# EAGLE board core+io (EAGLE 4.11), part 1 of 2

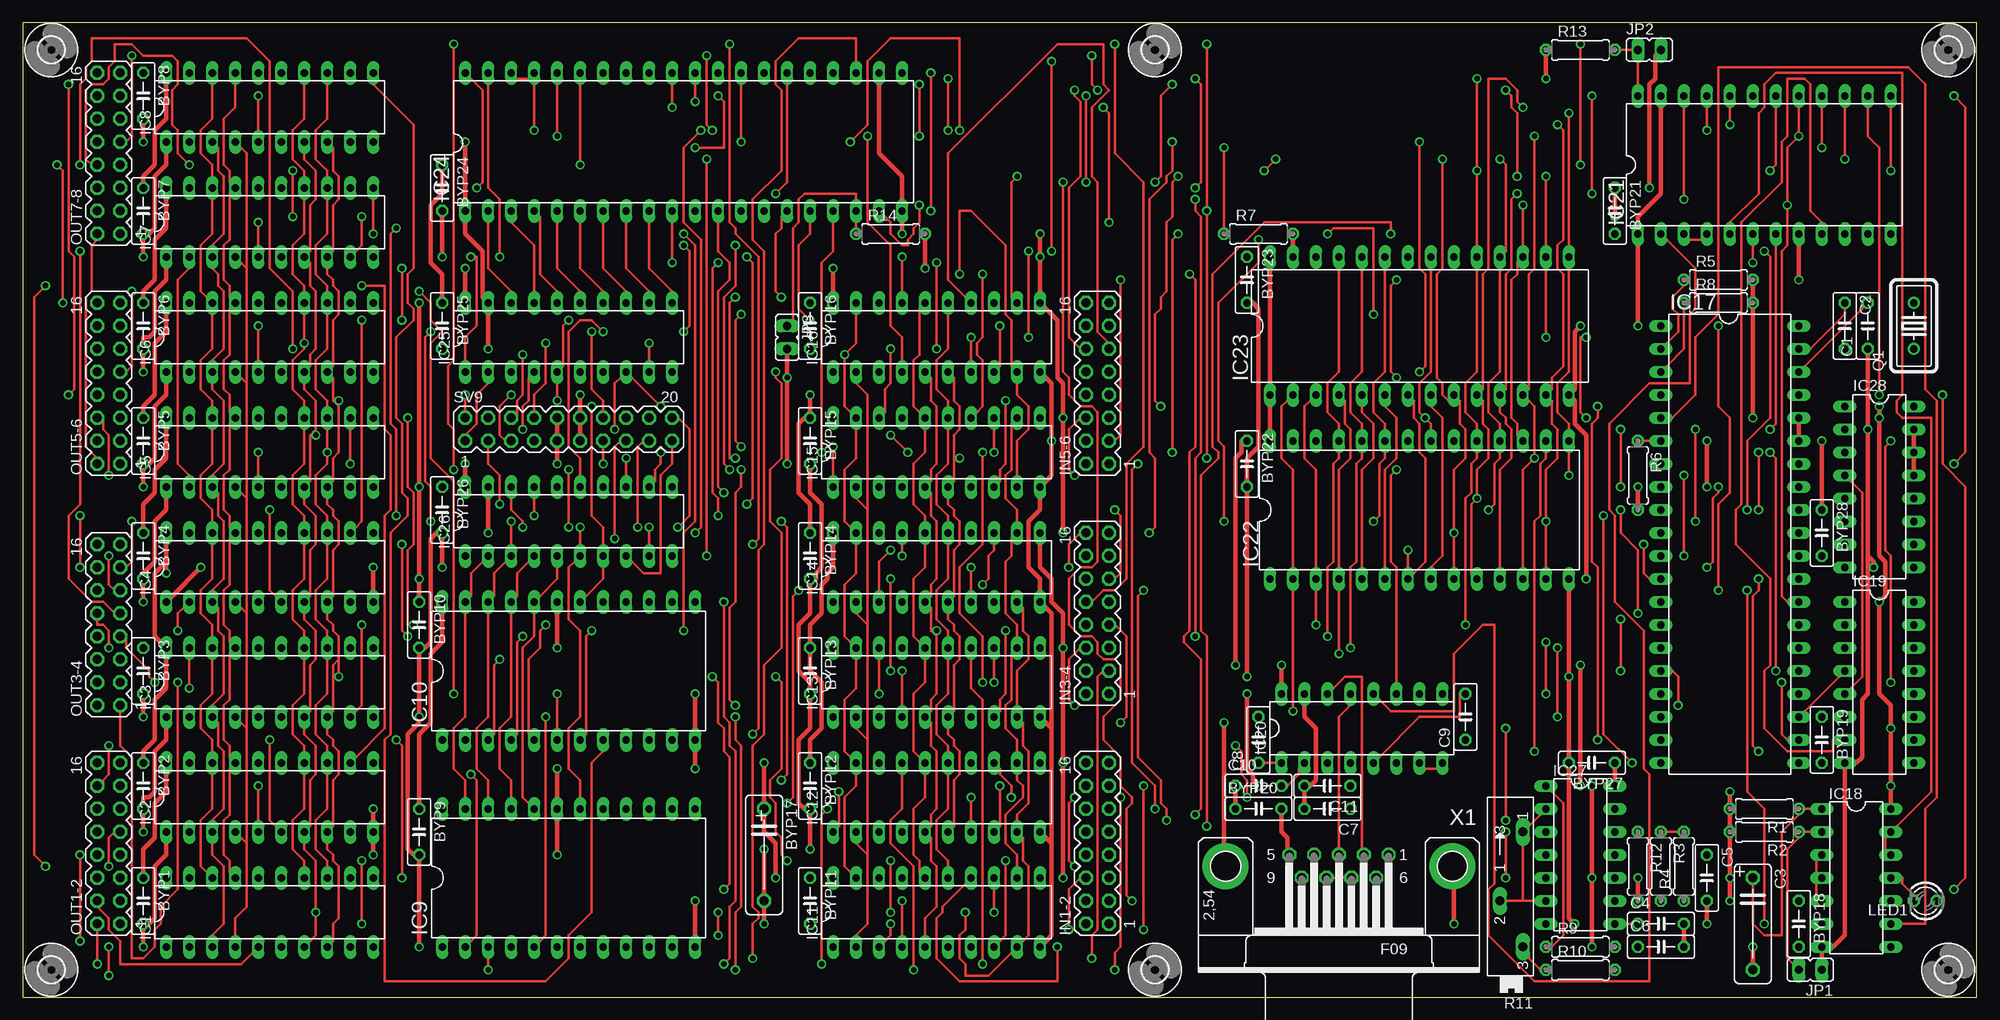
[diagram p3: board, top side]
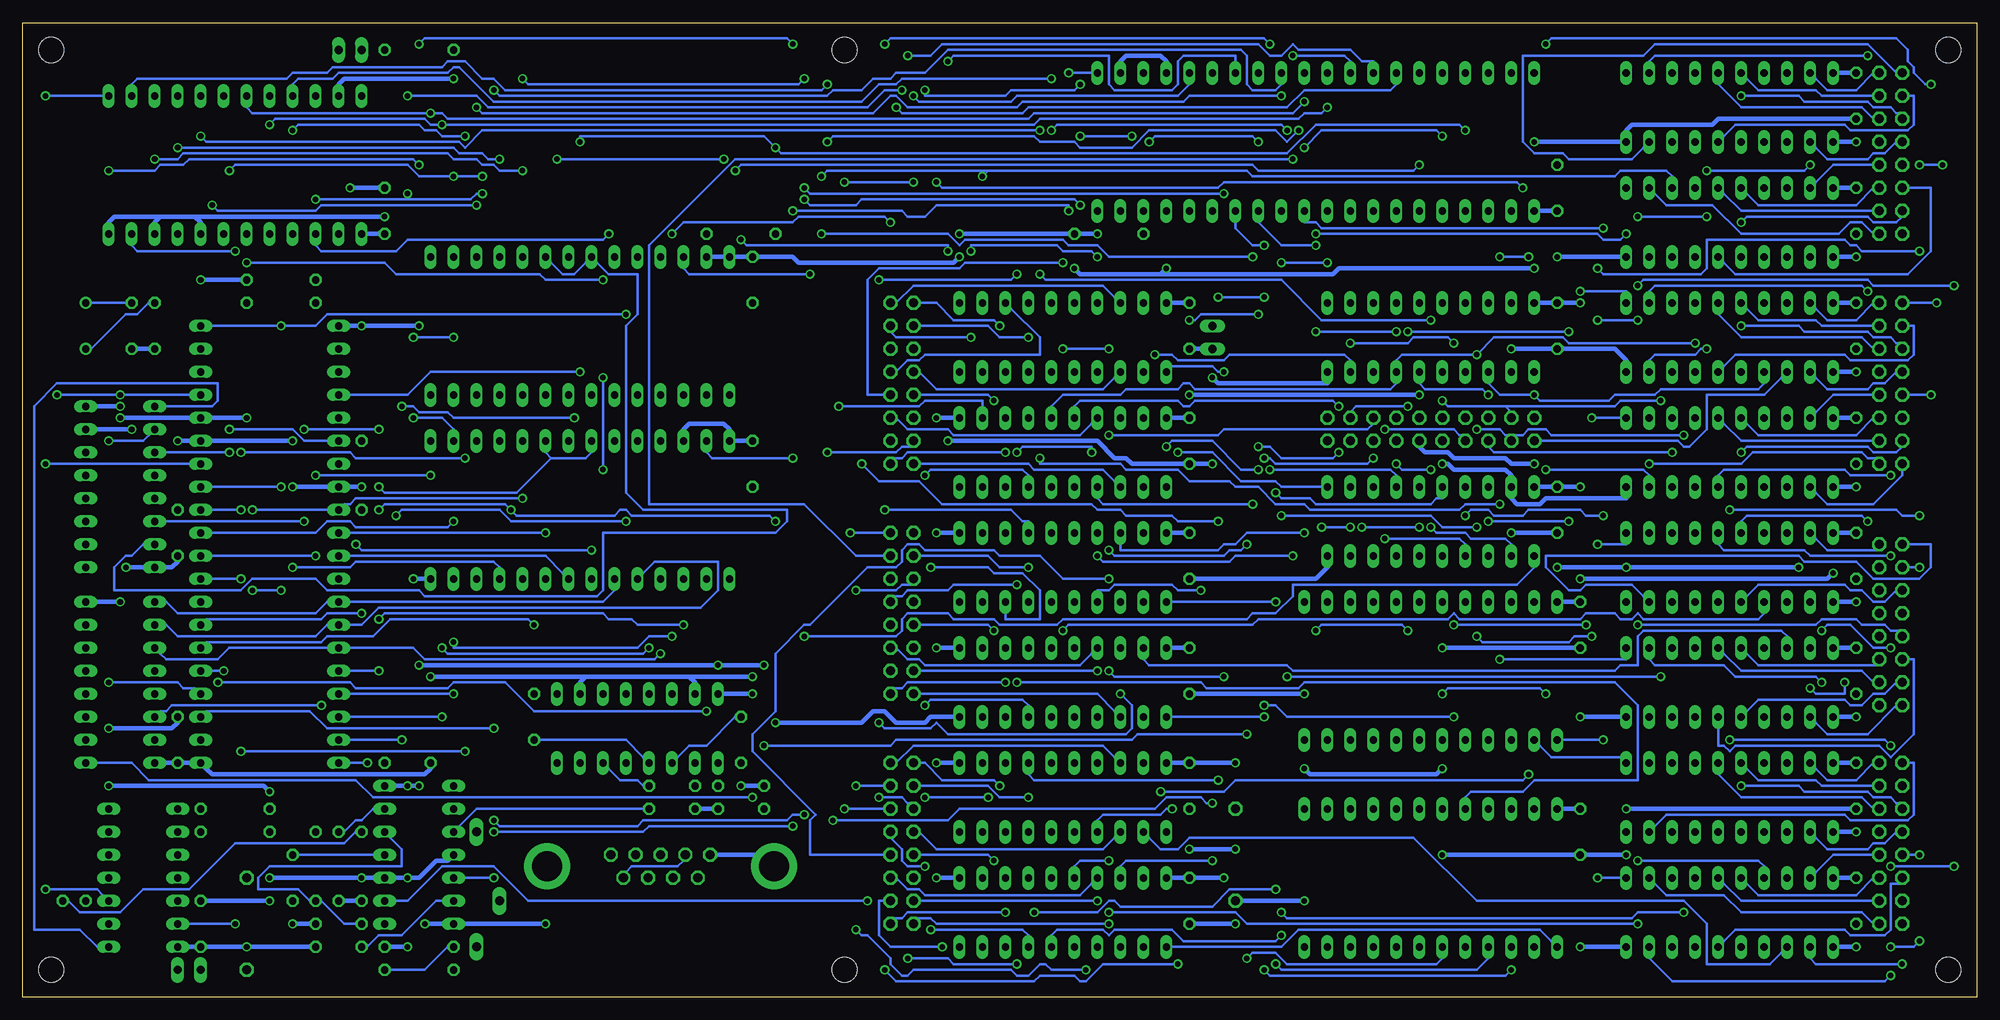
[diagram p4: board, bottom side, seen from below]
Size 215.88 x 107.62 mm. Coordinates in mm from the lower left corner, seen from the top.
Outline: 0,0 215.88,0 215.88,107.62 0,107.62 0,0
Copper layers (1*16): Top 0.035mm / dielectric 1.5mm / Bottom 0.035mm
Design rules "default": minimum track width 10mil, minimum drill 24mil, track to track 8mil, track to pad 8mil, pad to pad 8mil, via to via 8mil, smd to smd 8mil, copper to edge 40mil, drill to drill 8mil, minimum pad ring 10mil, minimum via ring 8mil, stop-mask expansion 4mil, vias tented up to drill 0mil, thermal gap 10mil
Net classes: 1 Power: width 0.508 mm, drill 0.254 mm, clearance 0.254 mm

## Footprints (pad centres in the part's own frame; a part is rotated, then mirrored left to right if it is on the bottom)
C050-025X075 = drill 0.813 octagon: 1 -2.54,0; 2 2.54,0
C102-043X133 = drill 1.016 octagon: 1 -5.08,0; 2 5.08,0
DIL20 = drill 0.813 long: 1 -11.43,-3.81; 2 -8.89,-3.81; 3 -6.35,-3.81; 4 -3.81,-3.81; 5 -1.27,-3.81; 6 1.27,-3.81; 7 3.81,-3.81; 8 6.35,-3.81; 9 8.89,-3.81; 10 11.43,-3.81; 11 11.43,3.81; 12 8.89,3.81; 13 6.35,3.81; 14 3.81,3.81; 15 1.27,3.81; 16 -1.27,3.81; 17 -3.81,3.81; 18 -6.35,3.81; 19 -8.89,3.81; 20 -11.43,3.81
DIL24-6 = drill 0.813 long: 1 -13.97,-7.62; 2 -11.43,-7.62; 3 -8.89,-7.62; 4 -6.35,-7.62; 5 -3.81,-7.62; 6 -1.27,-7.62; 7 1.27,-7.62; 8 3.81,-7.62; 9 6.35,-7.62; 10 8.89,-7.62; 11 11.43,-7.62; 12 13.97,-7.62; 13 13.97,7.62; 14 11.43,7.62; 15 8.89,7.62; 16 6.35,7.62; 17 3.81,7.62; 18 1.27,7.62; 19 -1.27,7.62; 20 -3.81,7.62; 21 -6.35,7.62; 22 -8.89,7.62; 23 -11.43,7.62; 24 -13.97,7.62
DIL40 = drill 0.813 long: 1 -24.13,-7.62; 2 -21.59,-7.62; 3 -19.05,-7.62; 4 -16.51,-7.62; 5 -13.97,-7.62; 6 -11.43,-7.62; 7 -8.89,-7.62; 8 -6.35,-7.62; 9 -3.81,-7.62; 10 -1.27,-7.62; 11 1.27,-7.62; 12 3.81,-7.62; 13 6.35,-7.62; 14 8.89,-7.62; 15 11.43,-7.62; 16 13.97,-7.62; 17 16.51,-7.62; 18 19.05,-7.62; 19 21.59,-7.62; 20 24.13,-7.62; 21 24.13,7.62; 22 21.59,7.62; 23 19.05,7.62; 24 16.51,7.62; 25 13.97,7.62; 26 11.43,7.62; 27 8.89,7.62; 28 6.35,7.62; 29 3.81,7.62; 30 1.27,7.62; 31 -1.27,7.62; 32 -3.81,7.62; 33 -6.35,7.62; 34 -8.89,7.62; 35 -11.43,7.62; 36 -13.97,7.62; 37 -16.51,7.62; 38 -19.05,7.62; 39 -21.59,7.62; 40 -24.13,7.62
DIL14 = drill 0.813 long: 1 -7.62,-3.81; 2 -5.08,-3.81; 3 -2.54,-3.81; 4 0,-3.81; 5 2.54,-3.81; 6 5.08,-3.81; 7 7.62,-3.81; 8 7.62,3.81; 9 5.08,3.81; 10 2.54,3.81; 11 0,3.81; 12 -2.54,3.81; 13 -5.08,3.81; 14 -7.62,3.81
DIL16 = drill 0.813 long: 1 -8.89,-3.81; 2 -6.35,-3.81; 3 -3.81,-3.81; 4 -1.27,-3.81; 5 1.27,-3.81; 6 3.81,-3.81; 7 6.35,-3.81; 8 8.89,-3.81; 9 8.89,3.81; 10 6.35,3.81; 11 3.81,3.81; 12 1.27,3.81; 13 -1.27,3.81; 14 -3.81,3.81; 15 -6.35,3.81; 16 -8.89,3.81
DIL24 = drill 0.813 long: 1 -13.97,-7.62; 2 -11.43,-7.62; 3 -8.89,-7.62; 4 -6.35,-7.62; 5 -3.81,-7.62; 6 -1.27,-7.62; 7 1.27,-7.62; 8 3.81,-7.62; 9 6.35,-7.62; 10 8.89,-7.62; 11 11.43,-7.62; 12 13.97,-7.62; 13 13.97,7.62; 14 11.43,7.62; 15 8.89,7.62; 16 6.35,7.62; 17 3.81,7.62; 18 1.27,7.62; 19 -1.27,7.62; 20 -3.81,7.62; 21 -6.35,7.62; 22 -8.89,7.62; 23 -11.43,7.62; 24 -13.97,7.62
DIL28-6 = drill 0.813 long: 1 -16.51,-7.62; 2 -13.97,-7.62; 3 -11.43,-7.62; 4 -8.89,-7.62; 5 -6.35,-7.62; 6 -3.81,-7.62; 7 -1.27,-7.62; 8 1.27,-7.62; 9 3.81,-7.62; 10 6.35,-7.62; 11 8.89,-7.62; 12 11.43,-7.62; 13 13.97,-7.62; 14 16.51,-7.62; 15 16.51,7.62; 16 13.97,7.62; 17 11.43,7.62; 18 8.89,7.62; 19 6.35,7.62; 20 3.81,7.62; 21 1.27,7.62; 22 -1.27,7.62; 23 -3.81,7.62; 24 -6.35,7.62; 25 -8.89,7.62; 26 -11.43,7.62; 27 -13.97,7.62; 28 -16.51,7.62
MA08-2 = drill 1.016 octagon: 1 -8.89,-1.27; 2 -8.89,1.27; 3 -6.35,-1.27; 4 -6.35,1.27; 5 -3.81,-1.27; 6 -3.81,1.27; 7 -1.27,-1.27; 8 -1.27,1.27; 9 1.27,-1.27; 10 1.27,1.27; 11 3.81,-1.27; 12 3.81,1.27; 13 6.35,-1.27; 14 6.35,1.27; 15 8.89,-1.27; 16 8.89,1.27
JP1 = drill 0.914 long: 1 0,-1.27; 2 0,1.27
LED3MM = drill 0.813 octagon: A -1.27,0; K 1.27,0
HC18U-V = drill 0.813 round: 1 -2.54,0; 2 2.54,0
0207/7 = drill 0.813 octagon: 1 -3.81,0; 2 3.81,0
SP19L = drill 1.016 long: A 5.715,-1.27; E -6.985,-1.27; S -1.905,1.27
MA10-2 = drill 1.016 octagon: 1 -11.43,-1.27; 2 -11.43,1.27; 3 -8.89,-1.27; 4 -8.89,1.27; 5 -6.35,-1.27; 6 -6.35,1.27; 7 -3.81,-1.27; 8 -3.81,1.27; 9 -1.27,-1.27; 10 -1.27,1.27; 11 1.27,-1.27; 12 1.27,1.27; 13 3.81,-1.27; 14 3.81,1.27; 15 6.35,-1.27; 16 6.35,1.27; 17 8.89,-1.27; 18 8.89,1.27; 19 11.43,-1.27; 20 11.43,1.27
2,8 = hole 2.8: 0,0
F09HP = drill 1.016 octagon: 1 -5.486,-1.27; 2 -2.743,-1.27; 3 0,-1.27; 4 2.743,-1.27; 5 5.486,-1.27; 6 -4.115,1.27; 7 -1.372,1.27; 8 1.372,1.27; 9 4.115,1.27 | drill 3.302 pad 5.08 round: G1 -12.522,0; G2 12.522,0

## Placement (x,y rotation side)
BYP1  .01uf  [C050-025X075]  13.33,10.63 270 top
BYP2  .01uf  [C050-025X075]  13.33,23.33 270 top
BYP3  .01uf  [C050-025X075]  13.33,36.03 270 top
BYP4  .01uf  [C050-025X075]  13.33,48.73 270 top
BYP5  .01uf  [C050-025X075]  13.33,61.43 270 top
BYP6  .01uf  [C050-025X075]  13.33,74.13 270 top
BYP7  .01uf  [C050-025X075]  13.33,86.83 270 top
BYP8  .01uf  [C050-025X075]  13.33,99.53 270 top
BYP9  .01uf  [C050-025X075]  43.81,18.25 270 top
BYP10  .01uf  [C050-025X075]  43.81,41.11 270 top
BYP11  .01uf  [C050-025X075]  86.99,10.63 270 top
BYP12  .01uf  [C050-025X075]  86.99,23.33 270 top
BYP13  .01uf  [C050-025X075]  86.99,36.03 270 top
BYP14  .01uf  [C050-025X075]  86.99,48.73 270 top
BYP15  .01uf  [C050-025X075]  86.99,61.43 270 top
BYP16  .01uf  [C050-025X075]  86.99,74.13 270 top
BYP17  100uf 25V  [C102-043X133]  81.91,15.71 270 top
BYP18  .01uf  [C050-025X075]  196.21,8.09 270 top
BYP19  .01uf  [C050-025X075]  198.75,28.41 270 top
BYP20  .01uf  [C050-025X075]  136.52,20.79 0 top
BYP21  .01uf  [C050-025X075]  175.89,86.83 270 top
BYP22  .01uf  [C050-025X075]  135.25,58.89 270 top
BYP23  .01uf  [C050-025X075]  135.25,79.21 270 top
BYP24  .01uf  [C050-025X075]  46.35,89.37 270 top
BYP25  .01uf  [C050-025X075]  46.35,74.13 270 top
BYP26  .01uf  [C050-025X075]  46.35,53.81 270 top
BYP27  .01uf  [C050-025X075]  173.35,25.87 180 top
BYP28  .01uf  [C050-025X075]  198.75,51.27 270 top
C1  27pf  [C050-025X075]  203.83,74.13 90 top
C2  27pf  [C050-025X075]  201.29,74.13 270 top
C3  22uf  [C102-043X133]  191.13,8.09 270 top
C4  0.1uf  [C050-025X075]  180.97,8.09 0 top
C5  .01uf  [C050-025X075]  186.05,13.17 270 top
C6  330pf  [C050-025X075]  180.97,5.55 0 top
C7  .01uf  [C050-025X075]  144.14,20.79 180 top
C8  0.1uf  [C050-025X075]  136.52,28.41 90 top
C9  0.1uf  [C050-025X075]  159.38,30.95 90 top
C10  0.1uf  [C050-025X075]  136.52,23.33 0 top
C11  0.1uf  [C050-025X075]  144.14,23.33 180 top
IC1  74LS374N  [DIL20]  27.3,9.36 0 top
IC2  74LS374N  [DIL20]  27.3,22.06 0 top
IC3  74LS374N  [DIL20]  27.3,34.76 0 top
IC4  74LS374N  [DIL20]  27.3,47.46 0 top
IC5  74LS374N  [DIL20]  27.3,60.16 0 top
IC6  74LS374N  [DIL20]  27.3,72.86 0 top
IC7  74LS374N  [DIL20]  27.3,85.56 0 top
IC8  74LS374N  [DIL20]  27.3,98.26 0 top
IC9  74154N  [DIL24-6]  60.32,13.17 0 top
IC10  74154N  [DIL24-6]  60.32,36.03 0 top
IC11  74LS373N  [DIL20]  100.96,9.36 0 top
IC12  74LS373N  [DIL20]  100.96,22.06 0 top
IC13  74LS373N  [DIL20]  100.96,34.76 0 top
IC14  74LS373N  [DIL20]  100.96,47.46 0 top
IC15  74LS373N  [DIL20]  100.96,60.16 0 top
IC16  74LS373N  [DIL20]  100.96,72.86 0 top
IC17  [DIL40]  188.59,50 270 top
IC18  74LS132N  [DIL14]  202.56,13.17 270 top
IC19  74LS138N  [DIL16]  205.1,34.76 270 top
IC20  MAX232  [DIL16]  147.95,29.68 0 top
IC21  [DIL24]  192.4,91.91 0 top
IC22  [DIL28-6]  154.3,53.81 0 top
IC23  27C128P  [DIL28-6]  154.3,74.13 0 top
IC24  [DIL40]  73.02,94.45 0 top
IC25  74LS245N  [DIL20]  60.32,72.86 0 top
IC26  74LS245N  [DIL20]  60.32,52.54 0 top
IC27  LM556N  [DIL14]  172.08,15.71 270 top
IC28  74LS139N  [DIL16]  205.1,56.35 270 top
IN1-2  [MA08-2]  118.74,16.98 90 top
IN3-4  [MA08-2]  118.74,42.38 90 top
IN5-6  [MA08-2]  118.74,67.78 90 top
JP1  RESET  [JP1]  197.48,3.01 90 top
JP2  DEBUG  [JP1]  179.7,104.61 270 top
JP3  CB1  [JP1]  84.45,72.86 180 top
LED1  [LED3MM]  210.18,10.63 180 top
OUT1-2  [MA08-2]  9.52,16.98 90 top
OUT3-4  [MA08-2]  9.52,41.11 90 top
OUT5-6  [MA08-2]  9.52,67.78 90 top
OUT7-8  [MA08-2]  9.52,93.18 90 top
Q1  4Mhz  [HC18U-V]  208.91,74.13 90 top
R1  10K  [0207/7]  192.4,20.79 180 top
R2  10K  [0207/7]  192.4,18.25 180 top
R3  100K  [0207/7]  180.97,14.44 270 top
R4  100K  [0207/7]  183.51,14.44 90 top
R5  3.3K  [0207/7]  187.32,79.21 0 top
R6  3.3K  [0207/7]  178.43,57.62 270 top
R7  3.3K  [0207/7]  136.52,84.29 0 top
R8  3.3K  [0207/7]  187.32,76.67 0 top
R9  1.8K  [0207/7]  172.08,5.55 0 top
R10  10K  [0207/7]  172.08,3.01 0 top
R11  10K  [SP19L]  164.46,12.54 90 top
R12  270  [0207/7]  178.43,14.44 270 top
R13  1K  [0207/7]  172.08,104.61 0 top
R14  3.3K  [0207/7]  95.88,84.29 0 top
SV9  [MA10-2]  60.32,62.7 0 top
U$1  [2,8]  125.09,3.01 0 top
U$2  [2,8]  125.09,104.61 0 top
U$3  [2,8]  3.17,104.61 0 top
U$4  [2,8]  3.17,3.01 0 top
U$5  [2,8]  212.72,104.61 0 top
U$6  [2,8]  212.72,3.01 0 top
X1  [F09HP]  145.41,14.44 180 top

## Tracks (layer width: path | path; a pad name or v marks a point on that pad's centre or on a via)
89AB\  (via drill 0.61)
  Top 0.254: v184.78,62.7 v184.78,52.54 | v176.53,56.35 v176.53,62.7
  Bottom 0.254: 157.47,59.52 158.11,60.16 IC22.20 | 157.47,59.52 153.66,59.52 153.03,60.16 IC22.22 | v184.78,52.54 200.02,52.54 IC28.6 | v176.53,62.7 v184.78,62.7 | v176.53,56.35 175.89,55.71 161.28,55.71 157.47,59.52
A00  (via drill 0.61)
  Top 0.254: IC22.10 160.01,46.82 160.01,54.45 v160.65,55.08 160.65,58.25 161.92,59.52 161.92,62.7 161.28,63.34 161.28,65.88 IC23.10 161.28,67.14 161.28,79.84 161.92,80.48 161.92,101.44 163.82,101.44 165.09,100.16 165.09,98.89 v165.73,98.26 | v192.4,82.39 193.03,81.75 193.03,63.97 190.5,61.43 v190.5,53.81 | v59.05,95.08 59.05,100.8 IC24.36 | v74.29,93.81 77.46,93.81 77.46,98.89 v76.83,99.53
  Bottom 0.254: v160.65,55.08 179.06,55.08 179.7,54.45 180.34,54.45 IC17.9 182.24,53.81 v190.5,53.81 | v192.4,82.39 203.19,82.39 203.83,83.02 IC21.11 | v59.05,95.08 59.69,95.72 72.38,95.72 v74.29,93.81 | v76.83,99.53 86.99,99.53 87.62,98.89 105.41,98.89 106.04,98.26 118.1,98.26 119.38,99.53 120.01,99.53 121.91,97.62 165.09,97.62 v165.73,98.26
A01  (via drill 0.61)
  Top 0.254: IC22.9 158.11,47.46 v158.11,51.27 158.11,58.25 159.38,59.52 159.38,62.7 158.75,63.34 158.75,65.88 IC23.9 157.47,65.88 156.84,66.51 156.84,67.78 156.2,68.41 156.2,79.84 156.84,80.48 v156.84,92.55 | v61.59,91.91 61.59,100.8 IC24.35 | v137.16,91.28 v138.42,92.55
  Bottom 0.254: v61.59,91.91 62.23,91.28 79.37,91.28 80,91.91 136.52,91.91 v137.16,91.28 | v138.42,92.55 v156.84,92.55 | v158.11,51.27 179.7,51.27 IC17.10
A02
  Top 0.254: IC23.8 155.57,65.24 156.84,63.97 156.84,48.73 155.57,47.46 IC22.8
  Bottom 0.254: IC22.8 156.2,46.82 158.11,48.73 179.7,48.73 IC17.11
A03  (via drill 0.61)
  Top 0.254: IC23.7 153.66,65.88 153.66,63.97 154.3,63.34 154.3,60.16 154.94,59.52 154.94,48.09 153.66,46.82 IC22.7 153.03,47.46 v153.03,49.37 | v179.06,50 179.06,46.82 179.7,46.19 IC17.12
  Bottom 0.254: v179.06,50 178.43,49.37 v153.03,49.37
A04
  Top 0.254: IC23.6 150.49,65.24 151.76,63.97 151.76,59.52 150.49,58.25 150.49,47.46 IC22.6
  Bottom 0.254: IC19.1 200.02,43.65 198.75,42.38 183.51,42.38 182.24,43.65 IC17.13 179.7,43.65 151.76,43.65 150.49,44.92 IC22.6
A05
  Top 0.254: IC22.5 147.95,47.46 147.95,58.25 149.22,59.52 149.22,63.34 147.95,64.61 147.95,65.24 IC23.5
  Bottom 0.254: IC19.2 200.02,41.11 198.75,39.84 183.51,39.84 182.24,41.11 IC17.14 179.7,41.11 178.43,41.11 176.53,43.02 140.97,43.02 139.06,44.92 139.06,48.09 146.04,48.09 147.31,46.82 IC22.5
A06  (via drill 0.61)
  Top 0.254: IC23.4 146.04,65.88 146.04,63.34 146.68,62.7 146.68,59.52 145.41,58.25 145.41,47.46 IC22.4 145.41,44.92 v145.41,37.94
  Bottom 0.254: IC19.3 200.66,37.94 200.02,37.3 194.31,37.3 193.03,38.57 182.24,38.57 IC17.15 179.7,38.57 172.72,38.57 171.44,37.3 146.04,37.3 v145.41,37.94
A07  (via drill 0.61)
  Top 0.254: IC23.3 142.23,65.88 141.6,65.24 141.6,59.52 142.87,58.25 142.87,47.46 IC22.3 142.87,44.92 v142.87,41.11 | v182.88,32.22 182.88,35.39 182.24,36.03 IC17.16 | v176.53,41.74 v176.53,36.03
  Bottom 0.254: v182.88,32.22 199.38,32.22 200.02,31.58 200.66,31.58 IC19.6 | v142.87,41.11 147.95,41.11 148.59,41.74 151.12,41.74 151.76,42.38 175.89,42.38 v176.53,41.74 | v176.53,36.03 179.7,36.03 IC17.16
A08  (via drill 0.61)
  Top 0.254: IC23.25 145.41,80.48 145.41,69.05 144.14,67.78 144.14,64.61 145.41,63.34 145.41,62.7 IC22.25 145.41,60.16 145.41,59.52 144.78,58.89 144.78,48.09 144.14,47.46 v144.14,39.84 | v168.27,39.2 v168.27,33.49
  Bottom 0.254: v168.27,33.49 179.7,33.49 IC17.17 | v168.27,39.2 168.27,38.57 147.95,38.57 146.68,39.84 v144.14,39.84
A09  (via drill 0.61)
  Top 0.254: IC23.24 147.95,80.48 147.95,69.05 146.68,67.78 146.68,64.61 147.95,63.34 147.95,62.7 IC22.24 147.95,60.16 147.95,59.52 147.31,58.89 147.31,48.09 146.68,47.46 v146.68,38.57 | v169.54,38.57 v169.54,30.95
  Bottom 0.254: v169.54,30.95 179.7,30.95 IC17.18 | v169.54,38.57 168.91,37.94 147.31,37.94 v146.68,38.57
A10  (via drill 0.61)
  Top 0.254: IC23.21 155.57,80.48 155.57,69.05 154.3,67.78 154.3,64.61 v154.94,63.97 155.57,63.34 155.57,62.7 IC22.21 | v173.98,28.41 173.98,47.46 173.35,48.09 173.35,63.34 173.98,63.97 v173.98,65.24
  Bottom 0.254: v173.98,28.41 179.7,28.41 IC17.19 | v173.98,65.24 172.72,65.24 172.08,64.61 168.91,64.61 168.27,63.97 v154.94,63.97
A11  (via drill 0.61)
  Top 0.254: IC23.23 150.49,80.48 150.49,69.05 149.22,67.78 149.22,64.61 150.49,63.34 150.49,62.7 IC22.23 150.49,60.16 150.49,59.52 149.85,58.89 149.85,53.17 v149.22,52.54 | v177.79,25.87 174.62,29.04 v174.62,53.17
  Bottom 0.254: v177.79,25.87 179.7,25.87 IC17.20 | v174.62,53.17 173.98,53.81 163.19,53.81 161.92,52.54 v149.22,52.54
A12  (via drill 0.61)
  Top 0.254: IC23.2 139.69,65.88 139.06,65.24 139.06,59.52 140.33,58.25 140.33,47.46 IC22.2 140.33,44.92 v140.33,31.58 | v194.31,34.76 194.31,29.04 194.94,28.41 IC17.22
  Bottom 0.254: v194.31,34.76 179.7,34.76 179.06,34.12 168.91,34.12 168.27,34.76 162.56,34.76 159.38,31.58 v140.33,31.58
A13  (via drill 0.61)
  Top 0.254: v128.9,79.84 129.53,79.21 129.53,60.8 128.9,60.16 128.9,40.48 128.27,39.84 128.27,39.2 130.17,37.3 130.17,20.79 v129.53,20.15 | v163.82,19.52 v163.82,29.68 | IC19.4 200.66,35.39 196.84,31.58 IC17.23
  Bottom 0.254: v128.9,79.84 142.23,79.84 142.87,80.48 IC23.26 | v129.53,20.15 130.81,20.15 131.44,19.52 147.31,19.52 147.95,18.88 163.19,18.88 v163.82,19.52 | v163.82,29.68 182.24,29.68 184.14,31.58 195.57,31.58 IC17.23
A14  (via drill 0.61)
  Top 0.254: v206.37,34.76 206.37,48.73 205.73,49.37 205.73,60.8 v206.37,61.43
  Bottom 0.254: v206.37,34.76 198.75,34.76 198.12,34.12 196.84,34.12 IC17.24 | v206.37,61.43 202.56,61.43 201.92,62.06 IC28.2
A15  (via drill 0.61)
  Top 0.254: v193.67,36.03 193.67,59.52 v193.03,60.16
  Bottom 0.254: v193.67,36.03 194.94,36.03 IC17.25 | v193.03,60.16 200.02,60.16 IC28.3
CB1
  Top 0.254: R14.1 92.07,84.92 92.07,85.56 IC24.18 92.07,88.1 92.07,88.73 86.35,88.73 85.72,88.1 85.72,85.56 85.08,84.92 85.08,74.77 JP3.1
CDEF\
  Bottom 0.254: IC23.20 157.47,81.11 156.2,79.84 154.94,79.84 153.66,81.11 IC23.22 152.39,81.11 151.12,79.84 147.95,79.84 147.95,75.4 149.22,74.13 149.22,55.71 147.31,53.81 131.44,53.81 131.44,52.54 132.71,51.27 151.76,51.27 151.76,44.92 152.39,44.28 171.44,44.28 172.08,44.92 182.24,44.92 183.51,46.19 190.5,46.19 191.76,44.92 205.73,44.92 205.73,47.46 204.47,48.73 203.83,48.73 202.56,50 IC28.7
D0  (via drill 0.61)
  Top 0.254: IC22.11 163.19,47.46 163.19,58.25 164.46,59.52 164.46,62.7 163.82,63.34 163.82,63.97 163.19,64.61 163.19,65.24 IC23.11 163.82,67.14 163.82,79.84 164.46,80.48 164.46,88.1 v165.09,88.73 | v183.51,88.1 183.51,98.26 IC21.22 | v118.1,103.97 118.1,100.8 v118.74,100.16 | v173.35,88.73 v173.35,99.53 | v187.32,56.35 187.32,55.71 186.69,55.08 186.69,48.09 v186.05,47.46
  Bottom 0.254: 173.35,88.1 166.37,88.1 165.73,88.73 v165.09,88.73 | 173.35,88.1 v183.51,88.1 | v118.1,103.97 115.56,103.97 114.3,105.25 79.37,105.25 78.1,103.97 76.83,103.97 75.56,105.25 74.92,104.61 69.21,104.61 67.94,103.34 66.67,103.34 IC24.33 | v118.74,100.16 120.64,100.16 122.55,98.26 164.46,98.26 165.73,99.53 v173.35,99.53 | v173.35,88.73 173.35,88.1 | v187.32,56.35 194.94,56.35 IC17.33 | v186.05,47.46 179.7,47.46 179.06,48.09 163.82,48.09 163.19,47.46 IC22.11
D1  (via drill 0.61)
  Top 0.254: IC22.12 165.73,47.46 165.73,58.25 v167,59.52 167,65.24 166.37,65.88 IC23.12 166.37,67.14 166.37,79.84 167,80.48 v167,95.08 | v186.05,95.72 186.05,98.26 IC21.21 | v75.56,103.97 75.56,96.36 v76.19,95.72 | v102.23,101.44 v102.23,95.72 | v191.76,60.16 v191.76,53.81
  Bottom 0.254: v186.05,95.72 185.41,96.36 172.08,96.36 171.44,95.72 170.17,95.72 169.54,95.08 v167,95.08 | v75.56,103.97 69.84,103.97 69.21,103.34 IC24.32 | v76.19,95.72 76.83,96.36 101.59,96.36 v102.23,95.72 | v102.23,101.44 118.74,101.44 119.38,100.8 121.28,100.8 123.19,98.89 163.82,98.89 167.63,102.7 168.27,102.7 168.91,102.07 180.97,102.07 181.6,101.44 185.41,101.44 186.05,100.8 IC21.21 | v191.76,53.81 194.94,53.81 IC17.32 | v191.76,60.16 179.7,60.16 179.06,59.52 v167,59.52
D2  (via drill 0.61)
  Top 0.254: IC22.13 168.27,47.46 v168.27,52.54 168.27,58.25 169.54,59.52 169.54,62.7 168.91,63.34 168.91,65.88 IC23.13 168.91,67.14 168.91,68.41 170.17,69.69 170.17,79.84 169.54,80.48 169.54,83.02 170.17,83.66 170.17,95.72 v169.54,96.36 | v188.59,96.36 188.59,98.26 IC21.20 | v71.75,98.26 71.75,100.8 IC24.31
  Bottom 0.254: v188.59,96.36 187.95,96.99 171.44,96.99 170.81,96.36 v169.54,96.36 104.13,96.36 103.5,96.99 74.92,96.99 74.29,97.62 72.38,97.62 v71.75,98.26 | v168.27,52.54 168.91,51.91 179.06,51.91 179.7,52.54 182.24,52.54 183.51,51.27 194.94,51.27 IC17.31
D3  (via drill 0.61)
  Top 0.254: v170.81,97.62 170.81,83.02 IC23.15 170.81,80.48 170.81,69.05 169.54,67.78 169.54,64.61 170.81,63.34 170.81,62.7 IC22.15 170.81,60.16 v170.81,57.62 | v74.29,98.89 74.29,100.8 IC24.30 | v183.51,57.62 v183.51,48.73
  Bottom 0.254: IC21.19 191.13,98.26 190.5,97.62 v170.81,97.62 169.54,97.62 168.91,96.99 104.77,96.99 104.13,97.62 75.56,97.62 v74.29,98.89 | v183.51,48.73 194.94,48.73 IC17.30 | v170.81,57.62 v183.51,57.62
D4  (via drill 0.61)
  Top 0.254: v168.27,72.86 168.27,80.48 IC23.16 168.27,83.02 v168.27,90.64 | v172.72,72.86 172.08,72.86 172.08,64.61 v172.72,63.97 | v193.03,91.28 193.67,91.91 193.67,98.26 IC21.18 | v163.82,100.16 164.46,99.53 164.46,98.26 165.09,97.62 v165.09,90.64 | v191.76,46.19 191.76,44.92 191.13,44.28 191.13,27.77 v191.76,27.14 | v167,27.14 167,52.54 167.63,53.17 167.63,58.89 168.27,59.52 168.27,60.16 IC22.16
  Bottom 0.254: v168.27,72.86 v172.72,72.86 | v172.72,63.97 169.54,63.97 168.27,62.7 IC22.16 | v193.03,91.28 192.4,91.91 173.35,91.91 172.08,90.64 v168.27,90.64 v165.09,90.64 | v163.82,100.16 163.19,99.53 126.99,99.53 126.36,100.16 123.19,100.16 121.91,101.44 120.01,101.44 119.38,102.07 116.2,102.07 113.66,104.61 81.27,104.61 80.64,103.97 80.64,100.8 80,100.16 77.46,100.16 76.83,100.8 IC24.29 | v191.76,46.19 194.94,46.19 IC17.29 | v167,27.14 v191.76,27.14
D5  (via drill 0.61)
  Top 0.254: IC22.17 165.09,62.06 165.09,63.34 164.46,63.97 164.46,79.21 165.09,79.84 165.09,81.11 IC23.17 165.73,83.02 v165.73,87.47 | v79.37,94.45 79.37,100.8 IC24.28 | v91.44,94.45 93.34,96.36 93.34,103.34 95.88,105.88 103.5,105.88 v103.5,95.72 | IC21.17 196.21,98.26 v196.21,95.08 194.94,93.81 v194.94,87.47 194.94,83.02 194.31,82.39 194.31,44.28 194.94,43.65 IC17.28
  Bottom 0.254: v79.37,94.45 80,95.08 90.8,95.08 v91.44,94.45 | v103.5,95.72 165.09,95.72 167,93.81 167.63,94.45 195.57,94.45 v196.21,95.08 | v165.73,87.47 182.88,87.47 183.51,86.83 194.31,86.83 v194.94,87.47
D6  (via drill 0.61)
  Top 0.254: v178.43,42.38 178.43,49.37 176.53,51.27 v176.53,53.81 | v161.92,53.81 162.56,54.45 162.56,58.89 163.19,59.52 163.19,60.16 IC22.18 163.19,62.7 163.19,63.34 161.92,64.61 161.92,67.78 163.19,69.05 163.19,80.48 IC23.18 163.82,82.39 163.82,91.91 v163.19,92.55 | v198.75,93.81 198.75,98.26 IC21.16 | v113.66,82.39 v113.66,103.34 | v136.52,83.66 136.52,81.11 132.07,76.67 132.07,61.43 132.71,60.8 v132.71,52.54
  Bottom 0.254: v178.43,42.38 182.24,42.38 182.88,41.74 195.57,41.74 IC17.27 | v176.53,53.81 175.89,54.45 162.56,54.45 v161.92,53.81 161.28,53.17 150.49,53.17 149.85,53.81 149.22,53.81 148.59,53.17 133.34,53.17 v132.71,52.54 | v198.75,93.81 168.27,93.81 167.63,93.18 165.09,93.18 164.46,92.55 v163.19,92.55 | v113.66,103.34 113.02,103.97 95.88,103.97 95.88,100.8 95.24,100.16 88.89,100.16 88.26,100.8 88.26,103.34 87.62,103.97 81.91,103.97 81.91,103.34 IC24.27 | v113.66,82.39 113.66,83.02 135.88,83.02 v136.52,83.66
D7  (via drill 0.61)
  Top 0.254: v159.38,41.11 159.38,55.08 160.01,55.71 160.01,58.89 160.65,59.52 160.65,60.16 IC22.19 160.65,62.7 160.65,63.34 159.38,64.61 159.38,67.78 160.65,69.05 160.65,80.48 IC23.19 160.65,83.02 v160.65,91.28 v160.65,101.44 | v201.29,92.55 201.29,98.26 IC21.15 | v83.18,88.73 84.45,90 84.45,100.8 IC24.26 | v129.53,89.37 130.17,90 130.17,100.8 v129.53,101.44
  Bottom 0.254: v159.38,41.11 160.01,41.74 175.25,41.74 177.16,39.84 182.24,39.84 182.88,39.2 195.57,39.2 IC17.26 | v201.29,92.55 198.75,92.55 198.12,93.18 168.91,93.18 168.27,92.55 165.73,92.55 165.09,91.91 163.82,91.91 163.19,91.28 v160.65,91.28 | v83.18,88.73 128.9,88.73 v129.53,89.37 | v129.53,101.44 130.17,100.8 160.01,100.8 v160.65,101.44
E  (via drill 0.61)
  Top 0.254: v205.1,66.51 205.1,93.81 203.83,95.08 203.83,98.26 IC21.14 | v117.47,90 v117.47,99.53 | v125.09,90 125.72,90.64 125.72,99.53 v126.99,100.8 | v213.35,11.9 214.62,13.17 214.62,56.35 212.09,58.89 v212.09,66.51
  Bottom 0.254: IC17.37 197.48,66.51 v205.1,66.51 v212.09,66.51 | v117.47,99.53 116.83,98.89 106.67,98.89 106.04,99.53 88.26,99.53 86.99,100.8 IC24.25 | v125.09,90 v117.47,90 | v126.99,100.8 127.63,100.16 162.56,100.16 163.82,101.44 165.09,101.44 167,103.34 168.91,103.34 169.54,102.7 181.6,102.7 182.24,102.07 186.05,102.07 186.69,101.44 203.19,101.44 203.83,100.8 IC21.14 | v213.35,11.9 207.64,11.9 207,11.27 IC18.10
GND  (via drill 0.61)
  Top 0.508: C6.2 183.51,6.18 183.51,7.46 C4.2 | v186.05,8.09 186.05,10 C5.2 | JP1.1 198.75,4.28 198.75,4.92 IC18.7 200.02,5.55 201.29,6.82 201.29,25.23 IC19.8 202.56,25.87 203.19,26.5 203.19,32.85 203.83,33.49 203.83,48.73 | v191.13,5.55 191.13,3.64 C3.2 | IC28.13 208.91,58.25 208.91,59.52 IC28.14 208.91,60.8 208.91,62.06 IC28.15 | C1.1 203.83,70.95 v203.83,62.7 203.83,48.73 | v204.47,47.46 204.47,48.09 203.83,48.73 | v168.27,101.44 168.27,103.97 R13.1 | v172.08,74.13 171.44,73.5 171.44,67.14 IC23.14 171.44,65.88 171.44,63.34 172.72,62.06 v172.72,46.19 | v178.43,74.13 178.43,83.02 IC21.1 178.43,85.56 178.43,86.19 180.97,88.73 180.97,98.26 IC21.23 | C7.2 141.6,21.42 141.6,22.7 C11.2 142.23,23.33 142.87,23.96 142.87,29.68 141.6,30.95 141.6,32.22 IC20.15 | X1.5 139.69,16.34 139.69,17.61 139.06,18.25 139.06,20.15 BYP20.2 | v158.11,8.09 158.11,12.54 X1.G1 | BYP23.2 135.88,76.67 136.52,76.03 136.52,60.8 135.25,59.52 135.25,56.98 BYP22.2 135.25,55.71 v135.25,35.39 | IC22.14 170.81,44.92 v170.81,35.39 170.81,26.5 BYP27.2 170.81,25.23 170.81,8.73 v171.44,8.09 | v74.29,10.63 74.29,6.82 IC9.12 | v81.91,8.09 81.91,10 BYP17.2 81.91,11.27 v81.91,16.34 | v74.29,33.49 74.29,29.68 IC10.12 74.29,27.14 v74.29,25.23 | v86.99,16.34 86.99,20.15 BYP12.2 86.35,20.79 85.72,21.42 85.72,28.41 86.99,29.68 86.99,32.85 BYP13.2 86.99,34.12 86.99,34.76 85.72,36.03 85.72,41.11 86.99,42.38 86.99,45.55 BYP14.2 87.62,46.19 87.62,46.82 88.26,47.46 88.26,54.45 86.99,55.71 86.99,58.25 BYP15.2 | 113.66,16.98 113.66,6.82 113.02,6.18 IC11.10 | 113.66,16.98 113.02,17.61 IC12.10 | 113.66,29.68 113.02,30.31 IC13.10
  Top 0.508: 113.66,29.68 113.66,16.98 | 113.66,29.68 113.66,42.38 113.02,43.02 IC14.10 112.39,44.92 112.39,46.19 111.12,47.46 111.12,52.54 112.39,53.81 112.39,55.08 IC15.10 113.02,56.98 113.66,57.62 v113.66,61.43 113.66,67.78 113.02,68.41 IC16.10 | v84.45,58.89 v84.45,68.41 84.45,70.95 JP3.2 | v51.43,71.59 51.43,75.4 IC25.19 50.8,77.3 50.8,82.39 48.89,84.29 48.89,85.56 IC24.1 48.89,88.1 v48.89,94.45 | v46.35,81.75 46.35,86.19 BYP24.2 | v13.33,81.75 13.33,83.66 BYP7.2 13.97,84.29 14.6,84.92 14.6,90.64 15.87,91.91 15.87,93.18 IC8.1 | v13.33,94.45 13.33,96.36 BYP8.2 | v13.33,69.05 13.33,70.95 BYP6.2 13.33,72.22 13.33,72.86 13.97,72.86 14.6,73.5 14.6,77.94 15.87,79.21 15.87,80.48 IC7.1 | v13.33,43.65 13.33,45.55 BYP4.2 13.33,46.82 14.6,48.09 14.6,52.54 15.87,53.81 15.87,55.08 IC5.1 | v13.33,56.35 13.33,58.25 BYP5.2 13.97,58.89 14.6,59.52 14.6,65.24 15.87,66.51 15.87,67.78 IC6.1 | v38.73,47.46 38.73,44.92 IC4.10 | v46.35,47.46 46.35,50.63 BYP26.2 45.72,51.27 45.08,50.63 45.08,39.2 44.45,38.57 BYP10.2 43.81,37.94 v43.81,30.95 43.81,30.31 42.54,29.04 42.54,16.34 43.18,15.71 BYP9.2 43.81,15.08 v43.81,5.55 | SV9.10 59.05,63.34 59.05,62.06 SV9.9 59.05,60.8 v59.05,58.89 | v51.43,51.27 51.43,55.08 IC26.19 | v59.05,38.57 59.05,42.38 IC10.19 | v13.33,30.95 13.33,32.85 BYP3.2 | v13.33,5.55 13.33,7.46 BYP1.2 13.97,8.09 14.6,8.73 14.6,14.44 15.87,15.71 15.87,16.98 IC2.1 | v13.33,18.25 13.33,20.15 BYP2.2 13.33,21.42 13.33,22.06 13.97,22.06 14.6,22.7 14.6,27.14 15.87,28.41 15.87,29.68 IC3.1 | v38.73,15.71 38.73,16.98 IC2.10 38.73,19.52 v38.73,20.79 | v59.05,15.71 59.05,19.52 IC9.19 59.05,22.06 v59.05,25.23
  Top 0.508: v19.68,47.46 16.5,44.28 IC4.1 | v132.71,30.31 132.71,16.34 X1.G2
  Bottom 0.508: v186.05,8.09 184.14,8.09 C4.2 | IC18.7 197.48,5.55 196.84,5.55 BYP18.2 195.57,5.55 v191.13,5.55 184.14,5.55 C6.2 | IC19.8 200.02,25.87 199.38,25.87 BYP19.2 198.12,25.87 197.48,25.87 IC17.21 195.57,25.23 194.94,24.6 171.44,24.6 170.81,25.23 BYP27.2 | BYP28.2 198.75,48.09 199.38,47.46 200.02,47.46 IC28.8 202.56,47.46 v204.47,47.46 | C2.2 201.92,71.59 203.19,71.59 C1.1 | v203.83,62.7 207.64,62.7 IC28.15 | v168.27,101.44 180.34,101.44 180.97,100.8 IC21.23 | BYP21.2 176.53,84.29 177.79,84.29 IC21.1 | v172.08,74.13 v178.43,74.13 179.7,74.13 IC17.1 | BYP20.2 139.69,20.79 140.97,20.79 C7.2 | X1.5 139.69,15.71 134.62,15.71 X1.G2 | v158.11,8.09 167,8.09 IC27.7 169.54,8.09 v171.44,8.09 | 142.23,35.39 141.6,34.76 IC20.15 | 153.66,35.39 142.23,35.39 | 153.66,35.39 154.3,34.76 IC20.10 | v170.81,35.39 153.66,35.39 | 142.23,35.39 v135.25,35.39 | v172.72,46.19 171.44,46.19 IC22.14 | v74.29,10.63 81.27,10.63 BYP17.2 | v81.91,8.09 86.35,8.09 BYP11.2 | v74.29,33.49 86.35,33.49 BYP13.2 | IC26.10 71.75,47.46 73.02,46.19 86.35,46.19 BYP14.2 | v86.99,16.34 v81.91,16.34 | v84.45,58.89 86.35,58.89 BYP15.2 87.62,58.89 93.34,58.89 93.97,59.52 95.24,59.52 97.15,61.43 v113.66,61.43 | v84.45,68.41 83.81,67.78 71.75,67.78 IC25.10 | BYP16.2 86.35,71.59 85.72,71.59 JP3.2 | IC6.10 38.73,70.32 40,71.59 45.72,71.59 BYP25.2 46.98,71.59 v51.43,71.59 | v46.35,81.75 39.37,81.75 IC7.10 | IC24.1 48.26,86.83 46.98,86.83 BYP24.2 | v48.89,94.45 39.37,94.45 IC8.10 38.73,95.72 38.1,96.36 29.2,96.36 28.57,96.99 13.97,96.99 BYP8.2 | v13.33,81.75 15.24,81.75 IC7.1 | v13.33,94.45 15.24,94.45 IC8.1 | v13.33,69.05 15.24,69.05 IC6.1
  Bottom 0.508: v13.33,43.65 15.24,43.65 IC4.1 | v13.33,56.35 15.24,56.35 IC5.1 | v46.35,47.46 v38.73,47.46 v19.68,47.46 | IC5.10 38.73,55.08 47.62,55.08 48.26,54.45 50.8,54.45 51.43,55.08 IC26.19 51.43,57.62 52.07,58.25 57.78,58.25 58.41,58.89 v59.05,58.89 | v51.43,51.27 46.98,51.27 BYP26.2 | v43.81,30.95 39.37,30.95 IC3.10 | v59.05,38.57 44.45,38.57 BYP10.2 | v13.33,30.95 15.24,30.95 IC3.1 | v13.33,5.55 15.24,5.55 IC1.1 | v13.33,18.25 15.24,18.25 IC2.1 | v38.73,15.71 43.18,15.71 BYP9.2 44.45,15.71 v59.05,15.71 | v43.81,5.55 39.37,5.55 IC1.10 | v38.73,20.79 13.97,20.79 BYP2.2 | v74.29,25.23 73.66,24.6 59.69,24.6 v59.05,25.23 | v132.71,30.31 123.19,30.31 121.91,31.58 120.64,31.58 119.38,30.31 116.2,30.31 115.56,30.95 113.02,30.95 IC13.10
HLT\
  Top 0.254: IC17.2 181.6,72.22 182.88,73.5 182.88,75.4 182.24,76.03 182.24,77.3 183.51,78.58 R5.1
IN00
  Bottom 0.254: IC9.1 46.98,6.18 48.26,7.46 74.92,7.46 76.83,5.55 88.89,5.55 IC11.1
IN01  (via drill 0.61)
  Top 0.254: v49.53,24.6 50.16,23.96 50.16,6.82 49.53,6.18 IC9.2 | v90.16,22.7 90.16,18.88 IC12.1
  Bottom 0.254: v49.53,24.6 50.16,23.96 81.91,23.96 83.18,22.7 v90.16,22.7
IN02  (via drill 0.61)
  Top 0.254: v51.43,3.01 51.43,4.28 IC9.3 | v78.73,3.01 78.73,9.36 79.37,10 79.37,27.77 78.73,28.41 v78.73,30.95
  Bottom 0.254: v51.43,3.01 52.07,2.38 78.1,2.38 v78.73,3.01 | v78.73,30.95 88.89,30.95 IC13.1
IN03  (via drill 0.61)
  Top 0.254: v77.46,3.64 78.1,4.28 78.1,10 78.73,10.63 78.73,27.14 78.1,27.77 78.1,30.31 77.46,30.95 v77.46,43.65
  Bottom 0.254: v77.46,3.64 76.83,3.01 55.24,3.01 53.97,4.28 IC9.4 | v77.46,43.65 88.89,43.65 IC14.1
IN04  (via drill 0.61)
  Top 0.254: v57.78,30.95 57.78,6.82 57.15,6.18 IC9.5 | v78.73,32.22 78.1,32.85 78.1,43.02 78.73,43.65 78.73,55.71 79.37,56.35 v79.37,58.25 | v89.53,60.8 89.53,57.62 IC15.1
  Bottom 0.254: v57.78,30.95 76.19,30.95 77.46,32.22 v78.73,32.22 | v79.37,58.25 81.27,58.25 84.45,61.43 88.89,61.43 v89.53,60.8
IN05  (via drill 0.61)
  Top 0.254: v80.64,4.28 80.64,8.09 81.27,8.73 81.27,9.36 80.64,10 80.64,27.77 81.91,29.04 81.91,36.66 83.81,38.57 83.81,51.27 82.55,52.54 82.55,58.25 83.81,59.52 83.81,67.78 83.18,68.41 v83.18,69.05
  Bottom 0.254: v80.64,4.28 80,4.92 77.46,4.92 76.19,3.64 59.69,3.64 59.05,4.28 IC9.6 | v83.18,69.05 83.81,69.05 84.45,69.69 88.89,69.69 IC16.1
IO-E\  (via drill 0.61)
  Top 0.254: v135.25,22.06 135.25,23.96 134.62,24.6 134.62,27.14 v133.98,27.77 | v80.64,29.04 81.27,29.68 81.27,49.37 81.91,50 81.91,82.39 80.64,83.66 80.64,88.1 83.81,91.28 83.81,100.16 83.18,100.8 83.18,103.34 85.72,105.88 92.07,105.88 92.07,103.34 IC24.23
  Bottom 0.254: v135.25,22.06 177.16,22.06 179.06,23.96 201.92,23.96 203.83,25.87 207.64,25.87 IC19.9 | v133.98,27.77 120.01,27.77 119.38,28.41 93.34,28.41 92.7,29.04 v80.64,29.04
IO-F\
  Top 0.254: IC21.9 198.75,85.56 197.48,86.83 197.48,100.8 196.84,101.44 194.94,101.44 194.94,95.08 194.31,94.45 194.31,90 189.86,85.56 189.86,54.45 189.22,53.81 189.22,50 193.03,46.19 193.03,36.66 192.4,36.03 192.4,29.68 194.94,27.14 200.02,27.14 200.02,28.41 IC19.7
IRQ\  (via drill 0.61)
  Top 0.254: IC24.38 54.61,101.44 55.88,101.44 IC24.37 56.51,100.8 v56.51,95.72 | v132.71,93.81 132.71,84.92 R7.1 | v154.3,69.05 154.94,69.69 154.94,79.84 154.3,80.48 v154.3,94.45
  Bottom 0.254: v56.51,95.72 57.15,96.36 73.02,96.36 76.19,93.18 132.07,93.18 v132.71,93.81 133.98,95.08 154.3,95.08 v154.3,94.45 | v154.3,69.05 170.81,69.05 173.35,66.51 179.7,66.51 IC17.4
MR
  Top 0.254: IC17.3 181.6,69.69 183.51,71.59 183.51,76.03 R8.1
N$1
  Bottom 0.254: IC12.3 95.24,17.61 96.52,16.34 114.93,16.34 116.83,18.25 IN1-2.10
N$2  (via drill 0.61)
  Top 0.254: v88.89,20.79 88.26,20.15 v88.26,3.64 | v120.64,3.01 120.64,4.92 121.28,5.55 v121.28,22.06
  Bottom 0.254: v88.89,20.79 89.53,20.79 90.16,20.15 96.52,20.15 97.15,19.52 IC12.4 | v88.26,3.64 96.52,3.64 98.42,1.74 99.05,1.74 99.69,2.38 103.5,2.38 104.13,1.74 119.38,1.74 v120.64,3.01 | v121.28,22.06 118.74,22.06 118.1,21.42 117.47,21.42 IN1-2.12
N$3
  Top 0.254: IC17.39 197.48,71.59 201.29,75.4 201.29,76.03 C2.1
  Bottom 0.254: Q1.1 208.28,71.59 204.47,75.4 203.19,75.4 201.92,76.67 C2.1
N$4
  Top 0.254: IC17.38 196.84,69.69 203.19,76.03 203.19,76.67 C1.2
  Bottom 0.254: Q1.2 208.28,76.67 204.47,76.67 C1.2
N$5
  Top 0.254: IC24.2 51.43,85.56 51.43,80.48 53.97,77.94 IC25.18
N$6
  Top 0.254: IC18.5 198.12,11.27 198.12,12.54 IC18.4 198.12,13.81 198.12,15.08 IC18.3
N$7  (via drill 0.61)
  Top 0.254: v104.77,22.06 104.77,19.52 IC12.7
  Bottom 0.254: v104.77,22.06 107.94,22.06 109.21,23.33 116.83,23.33 IN1-2.14
N$8  (via drill 0.61)
  Top 0.254: v107.94,23.33 107.94,18.88 IC12.8
  Bottom 0.254: v107.94,23.33 108.58,23.96 114.3,23.96 116.2,25.87 116.83,25.87 IN1-2.16
N$9  (via drill 0.61)
  Top 0.254: v108.58,15.08 108.58,6.82 107.94,6.18 IC11.8
  Bottom 0.254: v108.58,15.08 109.21,15.71 116.83,15.71 IN1-2.8
N$10  (via drill 0.61)
  Top 0.254: v115.56,7.46 115.56,11.9 116.83,13.17 IN1-2.6
  Bottom 0.254: v115.56,7.46 105.41,7.46 104.77,6.82 IC11.7
N$11  (via drill 0.61)
  Top 0.254: v97.15,10.63 97.15,6.82 IC11.4
  Bottom 0.254: v97.15,10.63 116.83,10.63 IN1-2.4
N$12  (via drill 0.61)
  Top 0.254: v95.88,8.09 95.88,6.82 95.24,6.18 IC11.3
  Bottom 0.254: v95.88,8.09 114.93,8.09 115.56,8.73 117.47,8.73 IN1-2.2
N$13  (via drill 0.61)
  Top 0.254: v107.31,9.36 107.31,11.9 IC11.13
  Bottom 0.254: v107.31,9.36 118.1,9.36 118.74,8.73 120.01,8.73 IN1-2.1
N$14  (via drill 0.61)
  Top 0.254: v114.3,5.55 114.3,1.74 103.5,1.74 100.96,4.28 100.96,8.73 101.59,9.36 101.59,10 104.13,12.54 IC11.14
  Bottom 0.254: v114.3,5.55 120.01,5.55 121.28,6.82 121.28,10.63 120.64,10.63 IN1-2.3
N$15
  Bottom 0.254: IC11.17 97.78,12.54 99.05,11.27 116.2,11.27 116.83,11.9 118.1,11.9 119.38,13.17 IN1-2.5
N$16  (via drill 0.61)
  Top 0.254: v84.45,15.08 83.81,15.71 83.81,17.61 83.18,18.25 83.18,21.42 82.55,22.06 82.55,23.96 83.81,25.23 83.81,34.76 v83.18,35.39 | v95.88,36.03 v95.88,46.19
  Bottom 0.254: v84.45,15.08 93.97,15.08 94.61,14.44 IC11.18 | v83.18,35.39 95.24,35.39 v95.88,36.03 | v95.88,46.19 100.96,46.19 103.5,48.73 107.94,48.73 108.58,49.37 116.2,49.37 116.83,50 118.1,50 118.74,49.37 118.74,48.09 119.38,47.46 122.55,47.46 128.9,41.11 129.53,41.11 132.71,37.94 132.71,31.58 135.25,29.04 135.25,27.14 128.27,20.15 128.9,19.52 128.9,15.71 120.64,15.71 IN1-2.7
N$17  (via drill 0.61)
  Top 0.254: v116.2,14.44 115.56,15.08 115.56,21.42 v116.2,22.06 | v109.21,22.06 109.21,23.33 107.94,24.6 107.94,25.23 IC12.13
  Bottom 0.254: v116.2,14.44 118.1,14.44 118.74,15.08 118.74,16.34 120.01,17.61 IN1-2.9 | v109.21,22.06 v116.2,22.06
N$18  (via drill 0.61)
  Top 0.254: v83.81,23.96 84.45,24.6 84.45,51.91 v83.81,52.54 | v123.19,58.89 122.55,58.25 122.55,25.87 125.09,23.33 v125.09,20.79
  Bottom 0.254: v83.81,23.96 104.13,23.96 104.77,24.6 IC12.14 | v83.81,52.54 88.26,52.54 88.89,53.17 93.97,53.17 94.61,53.81 97.15,53.81 97.78,54.45 114.3,54.45 116.83,56.98 121.28,56.98 v123.19,58.89 | v125.09,20.79 120.64,20.79 IN1-2.11
N$19  (via drill 0.61)
  Top 0.254: v123.82,7.46 v123.82,23.33 | v98.42,3.01 98.42,14.44 95.88,16.98 95.88,19.52 97.15,20.79 97.15,24.6 IC12.17
  Bottom 0.254: v123.82,23.33 120.64,23.33 IN1-2.13 | v123.82,7.46 123.19,6.82 122.55,6.82 120.01,4.28 120.01,3.64 118.74,2.38 118.1,2.38 117.47,3.01 106.67,3.01 106.04,2.38 104.77,2.38 103.5,3.64 102.86,3.64 102.23,3.01 v98.42,3.01
N$20
  Bottom 0.254: IC12.18 95.24,26.5 96.52,27.77 117.47,27.77 119.38,25.87 IN1-2.15
N$21
  Top 0.254: IC18.1 197.48,20.79 196.84,20.79 R1.1 196.21,20.15 194.31,18.25 194.31,6.82 192.4,6.82 191.13,8.09 191.13,12.54 C3.1
N$22
  Top 0.254: IC18.2 197.48,18.25 196.84,18.25 R2.1 196.21,17.61 194.94,16.34 194.94,4.28 195.57,3.64 JP1.2
N$23  (via drill 0.61)
  Top 0.254: IC21.4 185.41,83.66 184.14,83.66 IC21.3 | v163.82,18.25 v163.82,13.17 | v130.81,18.88 130.81,39.84 130.17,40.48 130.17,57.62 132.07,59.52 132.07,60.16 131.44,60.8 131.44,79.84 137.16,85.56 151.12,85.56 v151.12,84.29
  Bottom 0.254: v163.82,13.17 167,13.17 IC27.5 | v163.82,18.25 147.31,18.25 146.68,18.88 v130.81,18.88 | v151.12,84.29 151.76,83.66 173.35,83.66 174.62,82.39 182.88,82.39 183.51,83.02 IC21.3
N$24  (via drill 0.61)
  Top 0.254: v71.75,81.11 71.75,85.56 IC24.10 | v76.83,81.11 76.19,80.48 76.19,55.71 76.83,55.08 v76.83,53.17 | v55.24,51.91 55.24,52.54 53.97,53.81 53.97,55.08 IC26.18
  Bottom 0.254: v76.83,81.11 v71.75,81.11 | v76.83,53.17 60.32,53.17 59.05,51.91 v55.24,51.91
N$25  (via drill 0.61)
  Top 0.254: v56.51,53.17 56.51,55.08 IC26.17 | v41.27,53.17 41.27,62.7 40.64,63.34 40.64,84.29 v41.27,84.92
  Bottom 0.254: v56.51,53.17 55.88,53.81 53.97,53.81 53.34,53.17 50.16,53.17 49.53,53.81 43.81,53.81 43.18,53.17 v41.27,53.17 | v41.27,84.92 72.38,84.92 73.02,85.56 74.29,85.56 IC24.11
N$26
  Top 0.254: IC7.2 18.41,80.48 17.14,79.21 17.14,58.89 18.41,57.62 IC5.2 | OUT7-8.2 8.25,83.66 7.62,83.02 7.62,77.94 6.98,77.3 6.98,60.8 8.25,59.52 OUT5-6.2
  Bottom 0.254: IC5.2 17.77,55.71 16.5,54.45 11.43,54.45 8.25,57.62 8.25,58.25 OUT5-6.2
N$27
  Top 0.254: IC27.2 167.63,20.15 166.37,18.88 R11.A 165.73,16.98 165.73,10.63 | 165.73,10.63 163.82,10.63 R11.S | 165.73,10.63 167,10.63 IC27.6
  Bottom 0.254: C6.1 177.79,5.55 176.53,6.82 173.98,6.82 170.17,10.63 169.54,10.63 IC27.6
N$28
  Top 0.254: IC27.1 168.91,22.7 170.17,21.42 170.17,6.82 168.91,5.55 R9.1
  Bottom 0.254: R9.1 168.91,5.55 171.44,3.01 175.25,3.01 R10.2
N$29  (via drill 0.61)
  Top 0.254: v120.64,105.25 120.64,93.18 123.82,90 123.82,60.8 121.91,58.89 121.91,46.19 120.64,44.92 119.38,44.92 118.1,43.65 IN3-4.10 | v78.1,105.25 78.1,85.56 78.73,84.92 78.73,84.29 81.27,81.75 81.27,50.63 v80.64,50 | v95.88,49.37 94.61,48.09 94.61,44.92 IC14.3
  Bottom 0.254: v120.64,105.25 120.01,105.88 78.73,105.88 v78.1,105.25 | v80.64,50 81.27,49.37 82.55,49.37 83.18,48.73 95.24,48.73 v95.88,49.37
N$30  (via drill 0.61)
  Top 0.254: v123.82,44.92 123.19,44.28 123.19,26.5 125.72,23.96 125.72,21.42 126.36,20.79 v126.36,19.52 | v84.45,21.42 85.08,22.06 85.08,44.28 v85.72,44.92
  Bottom 0.254: v123.82,44.92 119.38,44.92 118.74,45.55 117.47,45.55 IN3-4.12 | v126.36,19.52 113.66,19.52 112.39,20.79 90.8,20.79 89.53,22.06 85.72,22.06 85.08,21.42 v84.45,21.42 | v85.72,44.92 88.26,44.92 88.89,45.55 95.24,45.55 95.88,44.92 97.15,44.92 IC14.4
N$31  (via drill 0.61)
  Top 0.254: v104.77,47.46 104.77,44.92 IC14.7
  Bottom 0.254: v104.77,47.46 107.94,47.46 109.21,48.73 116.83,48.73 IN3-4.14
N$32  (via drill 0.61)
  Top 0.254: v115.56,47.46 115.56,50 116.83,51.27 IN3-4.16
  Bottom 0.254: v115.56,47.46 109.21,47.46 108.58,46.82 105.41,46.82 103.5,44.92 103.5,41.74 107.31,41.74 107.31,42.38 IC14.8
N$33  (via drill 0.61)
  Top 0.254: v17.14,34.76 17.14,11.9 15.24,10 15.24,8.09 14.6,7.46 14.6,5.55 13.33,4.28 12.06,4.28 12.06,26.5 10.79,27.77 10.79,31.58 OUT3-4.1
  Bottom 0.254: v17.14,34.76 17.77,35.39 26.66,35.39 27.93,36.66 35.55,36.66 36.19,37.3 IC3.12
N$34
  Bottom 0.254: IC3.15 27.93,37.94 26.03,36.03 12.7,36.03 11.43,34.76 OUT3-4.3
N$35
  Bottom 0.254: IC3.16 25.39,37.94 24.12,36.66 10.79,36.66 OUT3-4.5
N$36  (via drill 0.61)
  Top 0.254: v14.6,34.76 13.97,35.39 13.97,36.03 11.43,38.57 11.43,39.84 OUT3-4.7 | v18.41,34.12 18.41,37.3 IC3.19
  Bottom 0.254: v14.6,34.76 14.6,33.49 17.77,33.49 v18.41,34.12
N$37
  Bottom 0.254: IC13.3 95.24,31.58 97.15,33.49 116.83,33.49 IN3-4.2
N$38  (via drill 0.61)
  Top 0.254: v97.15,36.03 97.15,32.22 IC13.4
  Bottom 0.254: v97.15,36.03 116.83,36.03 IN3-4.4
N$39  (via drill 0.61)
  Top 0.254: v116.2,32.22 115.56,32.85 115.56,37.3 116.83,38.57 IN3-4.6
  Bottom 0.254: v116.2,32.22 115.56,32.85 105.41,32.85 104.77,32.22 IC13.7
N$40  (via drill 0.61)
  Top 0.254: v108.58,40.48 108.58,33.49 107.94,32.85 107.94,31.58 IC13.8
  Bottom 0.254: v108.58,40.48 109.21,41.11 116.83,41.11 IN3-4.8
N$41  (via drill 0.61)
  Top 0.254: v106.04,45.55 106.67,46.19 106.67,48.73 107.31,49.37 107.31,50 IC14.13
  Bottom 0.254: v106.04,45.55 113.02,45.55 113.66,44.92 118.1,44.92 118.74,44.28 120.01,44.28 IN3-4.9
N$42  (via drill 0.61)
  Top 0.254: v120.64,53.81 121.28,53.17 121.28,46.82 120.64,46.19 IN3-4.11
  Bottom 0.254: v120.64,53.81 106.67,53.81 105.41,52.54 104.77,52.54 IC14.14
N$43  (via drill 0.61)
  Top 0.254: v97.15,48.73 97.15,50 IC14.17 | v75.56,48.73 v75.56,92.55
  Bottom 0.254: v97.15,48.73 96.52,48.09 82.55,48.09 81.91,48.73 v75.56,48.73 | v75.56,92.55 137.16,92.55 146.68,83.02 146.68,54.45 129.53,54.45 123.82,48.73 120.64,48.73 IN3-4.13
N$44  (via drill 0.61)
  Top 0.254: v124.45,51.27 125.09,51.91 125.09,59.52 124.45,60.16 124.45,88.1 126.36,90 126.36,90.64 126.99,91.28 v126.99,94.45 | v74.92,95.72 73.02,93.81 73.02,85.56 74.92,83.66 74.92,51.91 v74.29,51.27
  Bottom 0.254: v124.45,51.27 120.64,51.27 IN3-4.15 | v126.99,94.45 126.36,95.08 104.13,95.08 103.5,94.45 99.69,94.45 99.05,93.81 93.34,93.81 91.44,95.72 77.46,95.72 76.19,94.45 v74.92,95.72 | v74.29,51.27 80.64,51.27 81.91,50 83.18,50 83.81,49.37 94.61,49.37 94.61,50 IC14.18
N$45  (via drill 0.61)
  Top 0.254: v107.31,34.76 107.31,37.3 IC13.13
  Bottom 0.254: v107.31,34.76 118.1,34.76 118.74,34.12 120.01,34.12 IN3-4.1
N$46  (via drill 0.61)
  Top 0.254: v118.1,4.28 118.1,6.82 118.74,7.46 118.74,35.39 119.38,36.03 IN3-4.3 | v106.04,3.64 106.04,32.85 104.77,34.12 104.77,37.3 IC13.14
  Bottom 0.254: v118.1,4.28 113.66,4.28 113.02,3.64 v106.04,3.64
N$47
  Bottom 0.254: IC13.17 97.78,37.94 99.05,36.66 116.2,36.66 116.83,37.3 118.1,37.3 119.38,38.57 IN3-4.5
N$48  (via drill 0.61)
  Top 0.254: v121.28,30.31 121.91,30.95 121.91,39.84 120.64,41.11 IN3-4.7 | v94.61,33.49 94.61,37.3 IC13.18
  Bottom 0.254: v121.28,30.31 120.64,29.68 115.56,29.68 114.93,30.31 113.66,29.04 93.97,29.04 93.34,29.68 93.34,32.22 v94.61,33.49
N$49
  Bottom 0.254: IC3.5 25.39,31.58 24.12,32.85 14.6,32.85 13.97,32.22 12.7,32.22 11.43,33.49 10.16,33.49 8.89,34.76 OUT3-4.4
N$50
  Bottom 0.254: IC3.6 28.57,29.68 28.57,27.77 27.93,27.77 27.3,27.14 26.66,27.77 10.79,27.77 9.52,26.5 6.98,29.04 6.98,37.3 7.62,37.3 OUT3-4.6
N$51
  Bottom 0.254: IC3.2 17.77,30.31 16.5,29.04 12.06,29.04 8.89,32.22 OUT3-4.2
N$52  (via drill 0.61)
  Top 0.254: v37.46,41.11 37.46,32.22 36.83,31.58 IC3.9
  Bottom 0.254: v37.46,41.11 17.77,41.11 17.14,41.74 13.33,41.74 12.7,41.11 10.16,41.11 9.52,40.48 8.25,40.48 OUT3-4.8
N$53
  Bottom 0.254: IC1.12 35.55,12.54 34.29,11.27 27.93,11.27 26.03,9.36 12.7,9.36 11.43,8.09 OUT1-2.1
N$54
  Bottom 0.254: IC1.15 27.93,12.54 26.03,10.63 11.43,10.63 OUT1-2.3
N$55
  Bottom 0.254: IC1.16 25.39,12.54 24.12,11.27 13.33,11.27 11.43,13.17 OUT1-2.5
N$56
  Bottom 0.254: IC1.19 17.77,13.81 15.87,15.71 11.43,15.71 OUT1-2.7
N$57  (via drill 0.61)
  Top 0.254: v8.25,3.64 8.25,7.46 OUT1-2.2
  Bottom 0.254: v8.25,3.64 17.77,3.64 18.41,4.28 IC1.2
N$58
  Top 0.254: IC1.5 25.39,4.92 24.12,3.64 10.79,3.64 10.79,6.18 9.52,7.46 9.52,8.73 8.25,10 OUT1-2.4
N$59
  Bottom 0.254: IC1.6 27.93,6.18 26.66,7.46 14.6,7.46 13.97,6.82 10.16,6.82 9.52,7.46 9.52,12.54 8.25,12.54 OUT1-2.6
N$60  (via drill 0.61)
  Top 0.254: v6.34,6.18 v6.34,15.71 | v9.52,2.38 v9.52,5.55
  Bottom 0.254: v6.34,15.71 7.62,15.71 OUT1-2.8 | v6.34,6.18 6.98,5.55 v9.52,5.55 | v9.52,2.38 10.16,1.74 33.65,1.74 36.19,4.28 IC1.9
N$61
  Bottom 0.254: IC2.19 17.77,25.23 16.5,23.96 13.33,23.96 11.43,25.87 OUT1-2.15
N$62
  Bottom 0.254: IC2.16 25.39,25.23 24.12,23.96 17.77,23.96 17.14,23.33 11.43,23.33 OUT1-2.13
N$63
  Bottom 0.254: IC2.15 28.57,24.6 26.03,22.06 12.7,22.06 11.43,20.79 OUT1-2.11
N$64  (via drill 0.61)
  Top 0.254: v9.52,14.44 9.52,17.61 10.16,18.25 OUT1-2.9 | v2.54,14.44 1.27,15.71 1.27,77.3 v2.54,78.58 | v37.46,78.58 40,78.58 40,62.7 40.64,62.06 40.64,53.81 40,53.17 40,29.68 36.83,26.5 IC2.12
  Bottom 0.254: v2.54,14.44 v9.52,14.44 | v2.54,78.58 11.43,78.58 12.06,79.21 36.83,79.21 v37.46,78.58
N$65
  Bottom 0.254: IC2.2 17.77,17.61 16.5,16.34 12.06,16.34 11.43,16.98 10.16,16.98 8.89,18.25 OUT1-2.10
N$66  (via drill 0.61)
  Top 0.254: v26.03,23.33 26.03,19.52 IC2.5
  Bottom 0.254: v26.03,23.33 19.68,23.33 19.04,22.7 12.06,22.7 11.43,22.06 9.52,22.06 8.89,21.42 8.25,21.42 OUT1-2.12
N$67  (via drill 0.61)
  Top 0.254: v27.3,28.41 27.3,19.52 27.93,18.88 IC2.6 | v9.52,27.77 9.52,24.6 8.89,23.96 8.89,23.33 OUT1-2.14
  Bottom 0.254: v27.3,28.41 10.16,28.41 v9.52,27.77
N$68
  Bottom 0.254: IC2.9 35.55,18.88 34.29,20.15 14.6,20.15 13.97,19.52 7.62,19.52 6.98,20.15 6.98,25.87 7.62,25.87 OUT1-2.16
N$69  (via drill 0.61)
  Top 0.254: v17.14,40.48 17.14,42.38 17.77,43.02 IC4.2 | v9.52,38.57 9.52,40.48 8.89,41.11 8.25,41.11 8.25,41.74 OUT3-4.10
  Bottom 0.254: v17.14,40.48 16.5,41.11 13.97,41.11 11.43,38.57 v9.52,38.57
N$70
  Bottom 0.254: IC4.5 25.39,44.28 24.12,45.55 14.6,45.55 13.97,44.92 12.7,44.92 11.43,43.65 10.16,43.65 8.89,44.92 OUT3-4.12
N$71  (via drill 0.61)
  Top 0.254: v27.3,53.81 27.3,44.92 27.93,44.28 IC4.6 | v6.34,47.46 v6.34,53.17
  Bottom 0.254: v27.3,53.81 8.89,53.81 8.25,53.17 v6.34,53.17 | v6.34,47.46 7.62,47.46 OUT3-4.14
N$72
  Bottom 0.254: IC4.9 36.83,44.28 38.1,45.55 43.18,45.55 43.81,44.92 45.08,44.92 47.62,47.46 47.62,48.73 19.68,48.73 19.04,48.09 13.33,48.09 11.43,46.19 6.34,46.19 5.08,47.46 5.08,50 7.62,50 OUT3-4.16
N$73
  Bottom 0.254: IC4.19 17.77,50.63 16.5,49.37 10.79,49.37 OUT3-4.15
N$74  (via drill 0.61)
  Top 0.254: v12.06,52.54 12.06,48.09 11.43,47.46 OUT3-4.13
  Bottom 0.254: v12.06,52.54 12.7,53.17 25.39,53.17 26.03,52.54 IC4.16
N$75  (via drill 0.61)
  Top 0.254: v9.52,48.73 9.52,45.55 10.16,44.92 OUT3-4.11
  Bottom 0.254: v9.52,48.73 18.41,48.73 19.04,49.37 27.93,49.37 28.57,50 IC4.15
N$76  (via drill 0.61)
  Top 0.254: v37.46,74.77 37.46,52.54 36.83,51.91 IC4.12 | v41.91,80.48 v41.91,74.77 | v6.34,82.39 6.34,54.45 5.08,53.17 5.08,46.19 7.62,43.65 8.89,43.65 10.16,42.38 OUT3-4.9
  Bottom 0.254: v41.91,74.77 v37.46,74.77 | v41.91,80.48 41.27,79.84 30.47,79.84 29.84,80.48 29.84,83.66 14.6,83.66 13.97,83.02 13.33,83.02 12.7,82.39 v6.34,82.39
N$77
  Bottom 0.254: IC16.3 95.24,68.41 96.52,67.14 114.93,67.14 116.83,69.05 IN5-6.10
N$78  (via drill 0.61)
  Top 0.254: v116.2,100.16 116.2,99.53 116.83,98.89 116.83,90.64 115.56,89.37 115.56,72.86 116.83,71.59 IN5-6.12 | v99.05,95.08 v99.05,100.8 | v93.34,95.08 93.34,85.56 95.88,83.02 95.88,74.13 97.15,72.86 97.15,70.32 IC16.4
  Bottom 0.254: v116.2,100.16 116.2,99.53 107.31,99.53 106.67,100.16 99.69,100.16 v99.05,100.8 | v93.34,95.08 v99.05,95.08
N$79  (via drill 0.61)
  Top 0.254: v104.77,72.86 104.77,70.32 IC16.7
  Bottom 0.254: v104.77,72.86 107.94,72.86 109.21,74.13 116.83,74.13 IN5-6.14
N$80  (via drill 0.61)
  Top 0.254: v107.94,74.13 107.94,69.69 IC16.8
  Bottom 0.254: v107.94,74.13 108.58,74.77 113.02,74.77 114.93,76.67 116.83,76.67 IN5-6.16
N$81  (via drill 0.61)
  Top 0.254: v36.19,58.89 36.19,62.7 IC5.12
  Bottom 0.254: v36.19,58.89 26.03,58.89 24.76,60.16 12.7,60.16 12.06,59.52 10.79,59.52 OUT5-6.1
N$82
  Bottom 0.254: IC5.15 27.93,63.34 26.03,61.43 11.43,61.43 OUT5-6.3
N$83
  Bottom 0.254: IC5.16 25.39,63.34 24.12,62.06 13.33,62.06 11.43,63.97 OUT5-6.5
N$84
  Bottom 0.254: IC5.19 17.77,64.61 15.87,66.51 11.43,66.51 OUT5-6.7
N$85
  Bottom 0.254: IC7.12 35.55,88.73 34.29,87.47 29.2,87.47 26.03,84.29 15.24,84.29 13.97,85.56 12.7,85.56 11.43,84.29 OUT7-8.1
N$86
  Bottom 0.254: IC7.15 27.93,88.73 26.03,86.83 11.43,86.83 OUT7-8.3
N$87
  Bottom 0.254: IC7.16 25.39,88.73 24.12,87.47 13.33,87.47 11.43,89.37 OUT7-8.5
N$88
  Bottom 0.254: IC7.19 17.77,90 15.87,91.91 11.43,91.91 OUT7-8.7
N$89  (via drill 0.61)
  Top 0.254: v26.03,60.16 26.03,57.62 IC5.5
  Bottom 0.254: v26.03,60.16 25.39,60.8 12.06,60.8 11.43,60.16 8.89,60.16 8.25,60.8 OUT5-6.4
N$90  (via drill 0.61)
  Top 0.254: v9.52,57.62 9.52,62.06 8.89,62.7 8.89,63.97 OUT5-6.6
  Bottom 0.254: v9.52,57.62 13.97,57.62 14.6,58.25 27.93,58.25 28.57,57.62 IC5.6
N$91  (via drill 0.61)
  Top 0.254: v5.08,66.51 5.71,67.14 5.71,81.75 5.08,82.39 v5.08,100.8 | v47.62,105.25 47.62,70.32 46.98,69.69 46.98,63.34 47.62,62.7 v47.62,58.25
  Bottom 0.254: v5.08,66.51 7.62,66.51 OUT5-6.8 | v5.08,100.8 5.71,100.8 6.98,102.07 6.98,102.7 7.62,103.34 7.62,104.61 8.89,105.88 46.98,105.88 v47.62,105.25 | v47.62,58.25 36.83,58.25 36.19,57.62 IC5.9
N$92  (via drill 0.61)
  Top 0.254: v12.06,77.94 12.06,69.69 11.43,69.05 OUT5-6.9
  Bottom 0.254: v12.06,77.94 12.7,78.58 35.55,78.58 36.19,77.94 IC6.12
N$93
  Bottom 0.254: IC6.15 28.57,75.4 26.03,72.86 12.7,72.86 11.43,71.59 OUT5-6.11
N$94  (via drill 0.61)
  Top 0.254: v77.46,55.71 76.83,56.35 76.83,77.94 78.1,79.21 78.1,81.11 76.83,82.39 76.83,85.56 IC24.12
  Bottom 0.254: v77.46,55.71 76.83,55.08 73.66,55.08 73.02,54.45 60.32,54.45 59.69,55.08 59.05,55.08 IC26.16
N$95
  Bottom 0.254: IC6.16 25.39,76.03 24.12,74.77 17.77,74.77 17.14,74.13 11.43,74.13 OUT5-6.13
N$96
  Bottom 0.254: IC6.19 17.77,76.03 16.5,74.77 13.33,74.77 11.43,76.67 OUT5-6.15
N$97
  Bottom 0.254: IC6.2 17.77,68.41 16.5,67.14 12.06,67.14 11.43,67.78 10.16,67.78 8.89,69.05 OUT5-6.10
N$98  (via drill 0.61)
  Top 0.254: v26.03,74.13 26.03,70.32 IC6.5
  Bottom 0.254: v26.03,74.13 19.68,74.13 19.04,73.5 12.06,73.5 11.43,72.86 9.52,72.86 8.89,72.22 8.25,72.22 OUT5-6.12
N$99
  Bottom 0.254: IC6.6 27.93,69.69 26.66,70.95 14.6,70.95 13.97,70.32 7.62,70.32 6.98,70.95 6.98,74.13 7.62,74.13 OUT5-6.14
N$100  (via drill 0.61)
  Top 0.254: v29.84,71.59 29.84,77.94 27.3,80.48 27.3,103.34 24.76,105.88 7.62,105.88 7.62,103.34 6.98,102.7 6.98,101.44 6.34,100.8 v6.34,91.91 | v3.8,91.91 4.44,91.28 v4.44,76.67
  Bottom 0.254: v29.84,71.59 30.47,71.59 31.11,70.95 35.55,70.95 36.19,70.32 IC6.9 | v3.8,91.91 v6.34,91.91 | v4.44,76.67 7.62,76.67 OUT5-6.16
N$101
  Bottom 0.254: IC15.3 95.24,56.98 96.52,58.25 104.13,58.25 104.77,58.89 116.83,58.89 IN5-6.2
N$102  (via drill 0.61)
  Top 0.254: v80,54.45 80.64,55.08 80.64,81.11 v80,81.75 | v127.63,84.29 126.99,83.66 v126.99,60.16
  Bottom 0.254: v80,54.45 96.52,54.45 97.15,55.08 IC15.4 | v80,81.75 95.88,81.75 97.15,83.02 100.32,83.02 100.96,83.66 111.75,83.66 112.39,83.02 113.66,84.29 v127.63,84.29 | v126.99,60.16 119.38,60.16 118.74,60.8 117.47,60.8 IN5-6.4
N$103  (via drill 0.61)
  Top 0.254: v116.2,57.62 115.56,58.25 115.56,62.7 116.83,63.97 IN5-6.6
  Bottom 0.254: v116.2,57.62 115.56,58.25 105.41,58.25 104.77,57.62 IC15.7
N$104  (via drill 0.61)
  Top 0.254: v108.58,65.88 108.58,58.89 107.94,58.25 107.94,56.98 IC15.8
  Bottom 0.254: v108.58,65.88 109.21,66.51 116.83,66.51 IN5-6.8
N$105
  Bottom 0.254: IC16.13 106.67,76.03 103.5,72.86 103.5,70.95 116.2,70.95 116.83,70.32 118.1,70.32 119.38,69.05 IN5-6.9
N$106
  Top 0.254: IC16.14 104.13,77.3 102.23,79.21 102.23,93.18 114.3,105.25 119.38,105.25 119.38,100.8 120.01,100.16 118.1,98.26 118.1,90.64 118.74,90 118.74,73.5 120.01,72.22 IN5-6.11
N$107  (via drill 0.61)
  Top 0.254: v111.12,82.39 v111.12,72.86 | v97.15,81.75 97.15,77.94 IC16.17
  Bottom 0.254: v111.12,72.86 119.38,72.86 120.01,73.5 IN5-6.13 | v111.12,82.39 111.12,83.02 101.59,83.02 100.96,82.39 97.78,82.39 v97.15,81.75
N$108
